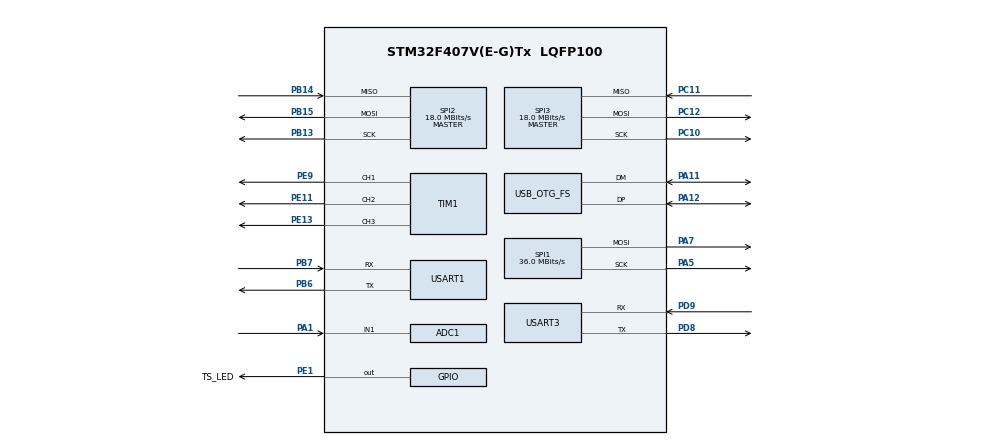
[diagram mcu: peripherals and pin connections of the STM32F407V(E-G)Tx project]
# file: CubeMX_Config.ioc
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ADC1.Channel-0\#ChannelRegularConversion=ADC_CHANNEL_1
ADC1.NbrOfConversionFlag=1
ADC1.Rank-0\#ChannelRegularConversion=1
ADC1.SamplingTime-0\#ChannelRegularConversion=ADC_SAMPLETIME_3CYCLES
ADC1.master=1
Mcu.Family=STM32F4
Mcu.Name=STM32F407V(E-G)Tx
Mcu.Package=LQFP100
NVIC.OTG_FS_IRQn=true\:0\:0\:false\:false\:true\:true\:true
NVIC.PriorityGroup=NVIC_PRIORITYGROUP_4
PA1.Signal=ADCx_IN1
PA11.Mode=Device_Only
PA11.Signal=USB_OTG_FS_DM
PA12.Mode=Device_Only
PA12.Signal=USB_OTG_FS_DP
PA13.Mode=Serial_Wire
PA13.Signal=SYS_JTMS-SWDIO
PA14.Mode=Serial_Wire
PA14.Signal=SYS_JTCK-SWCLK
PA5.Mode=TX_Only_Simplex_Unidirect_Master
PA5.Signal=SPI1_SCK
PA7.Mode=TX_Only_Simplex_Unidirect_Master
PA7.Signal=SPI1_MOSI
PB13.Mode=Full_Duplex_Master
PB13.Signal=SPI2_SCK
PB14.Mode=Full_Duplex_Master
PB14.Signal=SPI2_MISO
PB15.Mode=Full_Duplex_Master
PB15.Signal=SPI2_MOSI
PB6.Mode=Asynchronous
PB6.Signal=USART1_TX
PB7.Mode=Asynchronous
PB7.Signal=USART1_RX
PC10.Mode=Full_Duplex_Master
PC10.Signal=SPI3_SCK
PC11.Mode=Full_Duplex_Master
PC11.Signal=SPI3_MISO
PC12.Mode=Full_Duplex_Master
PC12.Signal=SPI3_MOSI
PC14-OSC32_IN.Mode=LSE-External-Oscillator
PC14-OSC32_IN.Signal=RCC_OSC32_IN
PC15-OSC32_OUT.Mode=LSE-External-Oscillator
PC15-OSC32_OUT.Signal=RCC_OSC32_OUT
PD8.Mode=Asynchronous
PD8.Signal=USART3_TX
PD9.Mode=Asynchronous
PD9.Signal=USART3_RX
PE1.GPIO_Label=TS_LED
PE1.Signal=GPIO_Output
PE11.Signal=S_TIM1_CH2
PE13.Signal=S_TIM1_CH3
PE9.Signal=S_TIM1_CH1
PH0-OSC_IN.Mode=HSE-External-Oscillator
PH0-OSC_IN.Signal=RCC_OSC_IN
PH1-OSC_OUT.Mode=HSE-External-Oscillator
PH1-OSC_OUT.Signal=RCC_OSC_OUT
ProjectManager.HeapSize=0x200
ProjectManager.StackSize=0x400
ProjectManager.TargetToolchain=MDK-ARM V5
RCC.48MHZClocksFreq_Value=48000000
RCC.AHBFreq_Value=72000000
RCC.APB1CLKDivider=RCC_HCLK_DIV2
RCC.APB1Freq_Value=36000000
RCC.APB1TimFreq_Value=72000000
RCC.APB2Freq_Value=72000000
RCC.APB2TimFreq_Value=72000000
RCC.CortexFreq_Value=72000000
RCC.HCLKFreq_Value=72000000
RCC.HSE_VALUE=12000000
RCC.HSI_VALUE=16000000
RCC.PLLM=6
RCC.PLLN=72
RCC.PLLQ=3
RCC.RCC_RTC_Clock_Source=RCC_RTCCLKSOURCE_LSI
RCC.RCC_RTC_Clock_SourceVirtual=RCC_RTCCLKSOURCE_LSE
RCC.SYSCLKFreq_VALUE=72000000
RCC.SYSCLKSource=RCC_SYSCLKSOURCE_PLLCLK
RCC.VCOOutputFreq_Value=144000000
SH.ADCx_IN1.0=ADC1_IN1,IN1
SH.S_TIM1_CH1.0=TIM1_CH1,PWM Generation1 CH1
SH.S_TIM1_CH2.0=TIM1_CH2,PWM Generation2 CH2
SH.S_TIM1_CH3.0=TIM1_CH3,PWM Generation3 CH3
SPI1.BaudRatePrescaler=SPI_BAUDRATEPRESCALER_2
SPI1.CalculateBaudRate=36.0 MBits/s
SPI1.Direction=SPI_DIRECTION_2LINES
SPI1.Mode=SPI_MODE_MASTER
SPI1.VirtualType=VM_MASTER
SPI2.BaudRatePrescaler=SPI_BAUDRATEPRESCALER_2
SPI2.CalculateBaudRate=18.0 MBits/s
SPI2.Direction=SPI_DIRECTION_2LINES
SPI2.Mode=SPI_MODE_MASTER
SPI2.VirtualType=VM_MASTER
SPI3.BaudRatePrescaler=SPI_BAUDRATEPRESCALER_2
SPI3.CalculateBaudRate=18.0 MBits/s
SPI3.Direction=SPI_DIRECTION_2LINES
SPI3.Mode=SPI_MODE_MASTER
SPI3.VirtualType=VM_MASTER
TIM1.Channel-PWM\ Generation1\ CH1=TIM_CHANNEL_1
TIM1.Channel-PWM\ Generation2\ CH2=TIM_CHANNEL_2
TIM1.Channel-PWM\ Generation3\ CH3=TIM_CHANNEL_3
USART1.VirtualMode=VM_ASYNC
USART3.VirtualMode=VM_ASYNC
USB_OTG_FS.VirtualMode=Device_Only
VP_RTC_VS_RTC_Activate.Mode=RTC_Enabled
VP_TIM1_VS_ClockSourceINT.Mode=Internal
board=custom

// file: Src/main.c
/* USER CODE BEGIN Header */
/**
  ******************************************************************************
  * @file           : main.c
  * @brief          : Main program body
  ******************************************************************************
  ** This notice applies to any and all portions of this file
  * that are not between comment pairs USER CODE BEGIN and
  * USER CODE END. Other portions of this file, whether
  * inserted by the user or by software development tools
  * are owned by their respective copyright owners.
  *
  * COPYRIGHT(c) 2018 STMicroelectronics
  *
  * Redistribution and use in source and binary forms, with or without modification,
  * are permitted provided that the following conditions are met:
  *   1. Redistributions of source code must retain the above copyright notice,
  *      this list of conditions and the following disclaimer.
  *   2. Redistributions in binary form must reproduce the above copyright notice,
  *      this list of conditions and the following disclaimer in the documentation
  *      and/or other materials provided with the distribution.
  *   3. Neither the name of STMicroelectronics nor the names of its contributors
  *      may be used to endorse or promote products derived from this software
  *      without specific prior written permission.
  *
  * THIS SOFTWARE IS PROVIDED BY THE COPYRIGHT HOLDERS AND CONTRIBUTORS "AS IS"
  * AND ANY EXPRESS OR IMPLIED WARRANTIES, INCLUDING, BUT NOT LIMITED TO, THE
  * IMPLIED WARRANTIES OF MERCHANTABILITY AND FITNESS FOR A PARTICULAR PURPOSE ARE
  * DISCLAIMED. IN NO EVENT SHALL THE COPYRIGHT HOLDER OR CONTRIBUTORS BE LIABLE
  * FOR ANY DIRECT, INDIRECT, INCIDENTAL, SPECIAL, EXEMPLARY, OR CONSEQUENTIAL
  * DAMAGES (INCLUDING, BUT NOT LIMITED TO, PROCUREMENT OF SUBSTITUTE GOODS OR
  * SERVICES; LOSS OF USE, DATA, OR PROFITS; OR BUSINESS INTERRUPTION) HOWEVER
  * CAUSED AND ON ANY THEORY OF LIABILITY, WHETHER IN CONTRACT, STRICT LIABILITY,
  * OR TORT (INCLUDING NEGLIGENCE OR OTHERWISE) ARISING IN ANY WAY OUT OF THE USE
  * OF THIS SOFTWARE, EVEN IF ADVISED OF THE POSSIBILITY OF SUCH DAMAGE.
  *
  ******************************************************************************
  */
/* USER CODE END Header */
#include "main.h"

ADC_HandleTypeDef hadc1;

RTC_HandleTypeDef hrtc;

SPI_HandleTypeDef hspi1;
SPI_HandleTypeDef hspi2;
SPI_HandleTypeDef hspi3;

TIM_HandleTypeDef htim1;

UART_HandleTypeDef huart1;
UART_HandleTypeDef huart3;

PCD_HandleTypeDef hpcd_USB_OTG_FS;

void SystemClock_Config(void);
static void MX_GPIO_Init(void);
static void MX_RTC_Init(void);
static void MX_SPI2_Init(void);
static void MX_USART1_UART_Init(void);
static void MX_USB_OTG_FS_PCD_Init(void);
static void MX_SPI1_Init(void);
static void MX_SPI3_Init(void);
static void MX_USART3_UART_Init(void);
static void MX_TIM1_Init(void);
static void MX_ADC1_Init(void);

int main(void)
{

  /* MCU Configuration--------------------------------------------------------*/

  /* Reset of all peripherals, Initializes the Flash interface and the Systick. */
  HAL_Init();

  /* Configure the system clock */
  SystemClock_Config();

  /* Initialize all configured peripherals */
  MX_GPIO_Init();
  MX_RTC_Init();
  MX_SPI2_Init();
  MX_USART1_UART_Init();
  MX_USB_OTG_FS_PCD_Init();
  MX_SPI1_Init();
  MX_SPI3_Init();
  MX_USART3_UART_Init();
  MX_TIM1_Init();
  MX_ADC1_Init();

  /* Infinite loop */
  while (1)
  {

  }
}

void SystemClock_Config(void)
{
  RCC_OscInitTypeDef RCC_OscInitStruct = {0};
  RCC_ClkInitTypeDef RCC_ClkInitStruct = {0};
  RCC_PeriphCLKInitTypeDef PeriphClkInitStruct = {0};

  /** Configure the main internal regulator output voltage
  */
  __HAL_RCC_PWR_CLK_ENABLE();
  __HAL_PWR_VOLTAGESCALING_CONFIG(PWR_REGULATOR_VOLTAGE_SCALE1);
  /** Initializes the RCC Oscillators according to the specified parameters
  * in the RCC_OscInitTypeDef structure.
  */
  RCC_OscInitStruct.OscillatorType = RCC_OSCILLATORTYPE_HSE|RCC_OSCILLATORTYPE_LSE;
  RCC_OscInitStruct.HSEState = RCC_HSE_ON;
  RCC_OscInitStruct.LSEState = RCC_LSE_ON;
  RCC_OscInitStruct.PLL.PLLState = RCC_PLL_ON;
  RCC_OscInitStruct.PLL.PLLSource = RCC_PLLSOURCE_HSE;
  RCC_OscInitStruct.PLL.PLLM = 6;
  RCC_OscInitStruct.PLL.PLLN = 168;
  RCC_OscInitStruct.PLL.PLLP = RCC_PLLP_DIV2;
  RCC_OscInitStruct.PLL.PLLQ = 7;
  if (HAL_RCC_OscConfig(&RCC_OscInitStruct) != HAL_OK)
  {
    Error_Handler();
  }
  /** Initializes the CPU, AHB and APB buses clocks
  */
  RCC_ClkInitStruct.ClockType = RCC_CLOCKTYPE_HCLK|RCC_CLOCKTYPE_SYSCLK
                              |RCC_CLOCKTYPE_PCLK1|RCC_CLOCKTYPE_PCLK2;
  RCC_ClkInitStruct.SYSCLKSource = RCC_SYSCLKSOURCE_PLLCLK;
  RCC_ClkInitStruct.AHBCLKDivider = RCC_SYSCLK_DIV2;
  RCC_ClkInitStruct.APB1CLKDivider = RCC_HCLK_DIV4;
  RCC_ClkInitStruct.APB2CLKDivider = RCC_HCLK_DIV2;

  if (HAL_RCC_ClockConfig(&RCC_ClkInitStruct, FLASH_LATENCY_2) != HAL_OK)
  {
    Error_Handler();
  }
  PeriphClkInitStruct.PeriphClockSelection = RCC_PERIPHCLK_RTC;
  PeriphClkInitStruct.RTCClockSelection = RCC_RTCCLKSOURCE_LSE;
  if (HAL_RCCEx_PeriphCLKConfig(&PeriphClkInitStruct) != HAL_OK)
  {
    Error_Handler();
  }
}

static void MX_ADC1_Init(void)
{

  ADC_ChannelConfTypeDef sConfig = {0};

  /** Configure the global features of the ADC (Clock, Resolution, Data Alignment and number of conversion)
  */
  hadc1.Instance = ADC1;
  hadc1.Init.ClockPrescaler = ADC_CLOCK_SYNC_PCLK_DIV2;
  hadc1.Init.Resolution = ADC_RESOLUTION_12B;
  hadc1.Init.ScanConvMode = DISABLE;
  hadc1.Init.ContinuousConvMode = DISABLE;
  hadc1.Init.DiscontinuousConvMode = DISABLE;
  hadc1.Init.ExternalTrigConvEdge = ADC_EXTERNALTRIGCONVEDGE_NONE;
  hadc1.Init.ExternalTrigConv = ADC_SOFTWARE_START;
  hadc1.Init.DataAlign = ADC_DATAALIGN_RIGHT;
  hadc1.Init.NbrOfConversion = 1;
  hadc1.Init.DMAContinuousRequests = DISABLE;
  hadc1.Init.EOCSelection = ADC_EOC_SINGLE_CONV;
  if (HAL_ADC_Init(&hadc1) != HAL_OK)
  {
    Error_Handler();
  }
  /** Configure for the selected ADC regular channel its corresponding rank in the sequencer and its sample time.
  */
  sConfig.Channel = ADC_CHANNEL_1;
  sConfig.Rank = 1;
  sConfig.SamplingTime = ADC_SAMPLETIME_3CYCLES;
  if (HAL_ADC_ConfigChannel(&hadc1, &sConfig) != HAL_OK)
  {
    Error_Handler();
  }

}

static void MX_RTC_Init(void)
{

  /** Initialize RTC Only
  */
  hrtc.Instance = RTC;
  hrtc.Init.HourFormat = RTC_HOURFORMAT_24;
  hrtc.Init.AsynchPrediv = 127;
  hrtc.Init.SynchPrediv = 255;
  hrtc.Init.OutPut = RTC_OUTPUT_DISABLE;
  hrtc.Init.OutPutPolarity = RTC_OUTPUT_POLARITY_HIGH;
  hrtc.Init.OutPutType = RTC_OUTPUT_TYPE_OPENDRAIN;
  if (HAL_RTC_Init(&hrtc) != HAL_OK)
  {
    Error_Handler();
  }

}

static void MX_SPI1_Init(void)
{

  /* SPI1 parameter configuration*/
  hspi1.Instance = SPI1;
  hspi1.Init.Mode = SPI_MODE_MASTER;
  hspi1.Init.Direction = SPI_DIRECTION_2LINES;
  hspi1.Init.DataSize = SPI_DATASIZE_8BIT;
  hspi1.Init.CLKPolarity = SPI_POLARITY_LOW;
  hspi1.Init.CLKPhase = SPI_PHASE_1EDGE;
  hspi1.Init.NSS = SPI_NSS_SOFT;
  hspi1.Init.BaudRatePrescaler = SPI_BAUDRATEPRESCALER_2;
  hspi1.Init.FirstBit = SPI_FIRSTBIT_MSB;
  hspi1.Init.TIMode = SPI_TIMODE_DISABLE;
  hspi1.Init.CRCCalculation = SPI_CRCCALCULATION_DISABLE;
  hspi1.Init.CRCPolynomial = 10;
  if (HAL_SPI_Init(&hspi1) != HAL_OK)
  {
    Error_Handler();
  }

}

static void MX_SPI2_Init(void)
{

  /* SPI2 parameter configuration*/
  hspi2.Instance = SPI2;
  hspi2.Init.Mode = SPI_MODE_MASTER;
  hspi2.Init.Direction = SPI_DIRECTION_2LINES;
  hspi2.Init.DataSize = SPI_DATASIZE_8BIT;
  hspi2.Init.CLKPolarity = SPI_POLARITY_LOW;
  hspi2.Init.CLKPhase = SPI_PHASE_1EDGE;
  hspi2.Init.NSS = SPI_NSS_SOFT;
  hspi2.Init.BaudRatePrescaler = SPI_BAUDRATEPRESCALER_2;
  hspi2.Init.FirstBit = SPI_FIRSTBIT_MSB;
  hspi2.Init.TIMode = SPI_TIMODE_DISABLE;
  hspi2.Init.CRCCalculation = SPI_CRCCALCULATION_DISABLE;
  hspi2.Init.CRCPolynomial = 10;
  if (HAL_SPI_Init(&hspi2) != HAL_OK)
  {
    Error_Handler();
  }

}

static void MX_SPI3_Init(void)
{

  /* SPI3 parameter configuration*/
  hspi3.Instance = SPI3;
  hspi3.Init.Mode = SPI_MODE_MASTER;
  hspi3.Init.Direction = SPI_DIRECTION_2LINES;
  hspi3.Init.DataSize = SPI_DATASIZE_8BIT;
  hspi3.Init.CLKPolarity = SPI_POLARITY_LOW;
  hspi3.Init.CLKPhase = SPI_PHASE_1EDGE;
  hspi3.Init.NSS = SPI_NSS_SOFT;
  hspi3.Init.BaudRatePrescaler = SPI_BAUDRATEPRESCALER_2;
  hspi3.Init.FirstBit = SPI_FIRSTBIT_MSB;
  hspi3.Init.TIMode = SPI_TIMODE_DISABLE;
  hspi3.Init.CRCCalculation = SPI_CRCCALCULATION_DISABLE;
  hspi3.Init.CRCPolynomial = 10;
  if (HAL_SPI_Init(&hspi3) != HAL_OK)
  {
    Error_Handler();
  }

}

static void MX_TIM1_Init(void)
{

  TIM_ClockConfigTypeDef sClockSourceConfig = {0};
  TIM_MasterConfigTypeDef sMasterConfig = {0};
  TIM_OC_InitTypeDef sConfigOC = {0};
  TIM_BreakDeadTimeConfigTypeDef sBreakDeadTimeConfig = {0};

  htim1.Instance = TIM1;
  htim1.Init.Prescaler = 0;
  htim1.Init.CounterMode = TIM_COUNTERMODE_UP;
  htim1.Init.Period = 65535;
  htim1.Init.ClockDivision = TIM_CLOCKDIVISION_DIV1;
  htim1.Init.RepetitionCounter = 0;
  htim1.Init.AutoReloadPreload = TIM_AUTORELOAD_PRELOAD_DISABLE;
  if (HAL_TIM_Base_Init(&htim1) != HAL_OK)
  {
    Error_Handler();
  }
  sClockSourceConfig.ClockSource = TIM_CLOCKSOURCE_INTERNAL;
  if (HAL_TIM_ConfigClockSource(&htim1, &sClockSourceConfig) != HAL_OK)
  {
    Error_Handler();
  }
  if (HAL_TIM_PWM_Init(&htim1) != HAL_OK)
  {
    Error_Handler();
  }
  sMasterConfig.MasterOutputTrigger = TIM_TRGO_RESET;
  sMasterConfig.MasterSlaveMode = TIM_MASTERSLAVEMODE_DISABLE;
  if (HAL_TIMEx_MasterConfigSynchronization(&htim1, &sMasterConfig) != HAL_OK)
  {
    Error_Handler();
  }
  sConfigOC.OCMode = TIM_OCMODE_PWM1;
  sConfigOC.Pulse = 0;
  sConfigOC.OCPolarity = TIM_OCPOLARITY_HIGH;
  sConfigOC.OCNPolarity = TIM_OCNPOLARITY_HIGH;
  sConfigOC.OCFastMode = TIM_OCFAST_DISABLE;
  sConfigOC.OCIdleState = TIM_OCIDLESTATE_RESET;
  sConfigOC.OCNIdleState = TIM_OCNIDLESTATE_RESET;
  if (HAL_TIM_PWM_ConfigChannel(&htim1, &sConfigOC, TIM_CHANNEL_1) != HAL_OK)
  {
    Error_Handler();
  }
  if (HAL_TIM_PWM_ConfigChannel(&htim1, &sConfigOC, TIM_CHANNEL_2) != HAL_OK)
  {
    Error_Handler();
  }
  if (HAL_TIM_PWM_ConfigChannel(&htim1, &sConfigOC, TIM_CHANNEL_3) != HAL_OK)
  {
    Error_Handler();
  }
  sBreakDeadTimeConfig.OffStateRunMode = TIM_OSSR_DISABLE;
  sBreakDeadTimeConfig.OffStateIDLEMode = TIM_OSSI_DISABLE;
  sBreakDeadTimeConfig.LockLevel = TIM_LOCKLEVEL_OFF;
  sBreakDeadTimeConfig.DeadTime = 0;
  sBreakDeadTimeConfig.BreakState = TIM_BREAK_DISABLE;
  sBreakDeadTimeConfig.BreakPolarity = TIM_BREAKPOLARITY_HIGH;
  sBreakDeadTimeConfig.AutomaticOutput = TIM_AUTOMATICOUTPUT_DISABLE;
  if (HAL_TIMEx_ConfigBreakDeadTime(&htim1, &sBreakDeadTimeConfig) != HAL_OK)
  {
    Error_Handler();
  }
  HAL_TIM_MspPostInit(&htim1);

}

static void MX_USART1_UART_Init(void)
{

  huart1.Instance = USART1;
  huart1.Init.BaudRate = 115200;
  huart1.Init.WordLength = UART_WORDLENGTH_8B;
  huart1.Init.StopBits = UART_STOPBITS_1;
  huart1.Init.Parity = UART_PARITY_NONE;
  huart1.Init.Mode = UART_MODE_TX_RX;
  huart1.Init.HwFlowCtl = UART_HWCONTROL_NONE;
  huart1.Init.OverSampling = UART_OVERSAMPLING_16;
  if (HAL_UART_Init(&huart1) != HAL_OK)
  {
    Error_Handler();
  }

}

static void MX_USART3_UART_Init(void)
{

  huart3.Instance = USART3;
  huart3.Init.BaudRate = 115200;
  huart3.Init.WordLength = UART_WORDLENGTH_8B;
  huart3.Init.StopBits = UART_STOPBITS_1;
  huart3.Init.Parity = UART_PARITY_NONE;
  huart3.Init.Mode = UART_MODE_TX_RX;
  huart3.Init.HwFlowCtl = UART_HWCONTROL_NONE;
  huart3.Init.OverSampling = UART_OVERSAMPLING_16;
  if (HAL_UART_Init(&huart3) != HAL_OK)
  {
    Error_Handler();
  }

}

static void MX_USB_OTG_FS_PCD_Init(void)
{

  hpcd_USB_OTG_FS.Instance = USB_OTG_FS;
  hpcd_USB_OTG_FS.Init.dev_endpoints = 4;
  hpcd_USB_OTG_FS.Init.speed = PCD_SPEED_FULL;
  hpcd_USB_OTG_FS.Init.dma_enable = DISABLE;
  hpcd_USB_OTG_FS.Init.phy_itface = PCD_PHY_EMBEDDED;
  hpcd_USB_OTG_FS.Init.Sof_enable = DISABLE;
  hpcd_USB_OTG_FS.Init.low_power_enable = DISABLE;
  hpcd_USB_OTG_FS.Init.lpm_enable = DISABLE;
  hpcd_USB_OTG_FS.Init.vbus_sensing_enable = DISABLE;
  hpcd_USB_OTG_FS.Init.use_dedicated_ep1 = DISABLE;
  if (HAL_PCD_Init(&hpcd_USB_OTG_FS) != HAL_OK)
  {
    Error_Handler();
  }

}

static void MX_GPIO_Init(void)
{
  GPIO_InitTypeDef GPIO_InitStruct = {0};

  /* GPIO Ports Clock Enable */
  __HAL_RCC_GPIOC_CLK_ENABLE();
  __HAL_RCC_GPIOH_CLK_ENABLE();
  __HAL_RCC_GPIOA_CLK_ENABLE();
  __HAL_RCC_GPIOE_CLK_ENABLE();
  __HAL_RCC_GPIOB_CLK_ENABLE();
  __HAL_RCC_GPIOD_CLK_ENABLE();

  /*Configure GPIO pin Output Level */
  HAL_GPIO_WritePin(TS_LED_GPIO_Port, TS_LED_Pin, GPIO_PIN_RESET);

  /*Configure GPIO pin : TS_LED_Pin */
  GPIO_InitStruct.Pin = TS_LED_Pin;
  GPIO_InitStruct.Mode = GPIO_MODE_OUTPUT_PP;
  GPIO_InitStruct.Pull = GPIO_NOPULL;
  GPIO_InitStruct.Speed = GPIO_SPEED_FREQ_LOW;
  HAL_GPIO_Init(TS_LED_GPIO_Port, &GPIO_InitStruct);

}

void Error_Handler(void)
{
}

/************************ (C) COPYRIGHT STMicroelectronics *****END OF FILE****/
